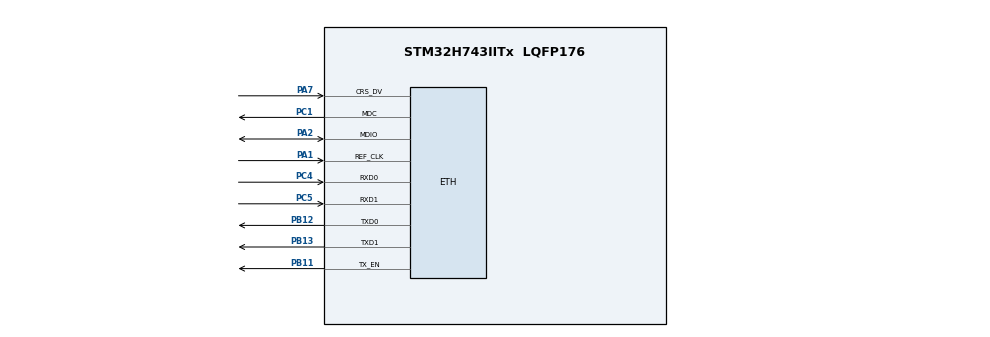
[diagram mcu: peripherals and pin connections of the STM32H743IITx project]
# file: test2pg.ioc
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CORTEX_M7.BaseAddress-Cortex_Memory_Protection_Unit_Region0_Settings=0x30040000
CORTEX_M7.BaseAddress-Cortex_Memory_Protection_Unit_Region1_Settings=0x30040000
CORTEX_M7.CPU_DCache=Enabled
CORTEX_M7.CPU_ICache=Enabled
CORTEX_M7.DisableExec-Cortex_Memory_Protection_Unit_Region0_Settings=MPU_INSTRUCTION_ACCESS_DISABLE
CORTEX_M7.DisableExec-Cortex_Memory_Protection_Unit_Region1_Settings=MPU_INSTRUCTION_ACCESS_ENABLE
CORTEX_M7.Enable-Cortex_Memory_Protection_Unit_Region0_Settings=MPU_REGION_ENABLE
CORTEX_M7.Enable-Cortex_Memory_Protection_Unit_Region1_Settings=MPU_REGION_ENABLE
CORTEX_M7.IsBufferable-Cortex_Memory_Protection_Unit_Region0_Settings=MPU_ACCESS_BUFFERABLE
CORTEX_M7.IsBufferable-Cortex_Memory_Protection_Unit_Region1_Settings=MPU_ACCESS_NOT_BUFFERABLE
CORTEX_M7.IsCacheable-Cortex_Memory_Protection_Unit_Region1_Settings=MPU_ACCESS_CACHEABLE
CORTEX_M7.IsShareable-Cortex_Memory_Protection_Unit_Region0_Settings=MPU_ACCESS_SHAREABLE
CORTEX_M7.IsShareable-Cortex_Memory_Protection_Unit_Region1_Settings=MPU_ACCESS_NOT_SHAREABLE
CORTEX_M7.MPU_Control=MPU_PRIVILEGED_DEFAULT
CORTEX_M7.Size-Cortex_Memory_Protection_Unit_Region0_Settings=MPU_REGION_SIZE_256B
CORTEX_M7.Size-Cortex_Memory_Protection_Unit_Region1_Settings=MPU_REGION_SIZE_16KB
ETH.MediaInterface=HAL_ETH_RMII_MODE
FREERTOS.Tasks01=defaultTask,0,1024,StartDefaultTask,Default,NULL,Dynamic,NULL,NULL
LWIP.BSP.number=1
LWIP.MEM_SIZE=16360
LWIP.Version=v2.1.2_Cube
LWIP0.BSP.STBoard=false
LWIP0.BSP.api=BSP_COMPONENT_DRIVER
LWIP0.BSP.component=LAN8742
LWIP0.BSP.i2caddr=0
LWIP0.BSP.instance=LAN8742
LWIP0.BSP.name=Driver_PHY
LWIP0.BSP.solution=LAN8742
Mcu.Family=STM32H7
Mcu.Name=STM32H743IITx
Mcu.Package=LQFP176
NVIC.ETH_IRQn=true\:5\:0\:false\:false\:true\:true\:true\:true
NVIC.PriorityGroup=NVIC_PRIORITYGROUP_4
PA1.Mode=RMII
PA1.Signal=ETH_REF_CLK
PA2.Mode=RMII
PA2.Signal=ETH_MDIO
PA7.Mode=RMII
PA7.Signal=ETH_CRS_DV
PB11.Mode=RMII
PB11.Signal=ETH_TX_EN
PB12.Mode=RMII
PB12.Signal=ETH_TXD0
PB13.Mode=RMII
PB13.Signal=ETH_TXD1
PC1.Mode=RMII
PC1.Signal=ETH_MDC
PC4.Mode=RMII
PC4.Signal=ETH_RXD0
PC5.Mode=RMII
PC5.Signal=ETH_RXD1
PH0-OSC_IN\ (PH0).Mode=HSE-External-Oscillator
PH0-OSC_IN\ (PH0).Signal=RCC_OSC_IN
PH1-OSC_OUT\ (PH1).Mode=HSE-External-Oscillator
PH1-OSC_OUT\ (PH1).Signal=RCC_OSC_OUT
ProjectManager.HeapSize=0x200
ProjectManager.StackSize=0x400
ProjectManager.TargetToolchain=STM32CubeIDE
RCC.ADCFreq_Value=50390625
RCC.APB1Freq_Value=120000000
RCC.APB2Freq_Value=120000000
RCC.APB3Freq_Value=120000000
RCC.APB4Freq_Value=120000000
RCC.CortexFreq_Value=480000000
RCC.D1PPRE=RCC_APB3_DIV2
RCC.D2PPRE1=RCC_APB1_DIV2
RCC.D2PPRE2=RCC_APB2_DIV2
RCC.D3PPRE=RCC_APB4_DIV2
RCC.DIVM1=5
RCC.DIVN1=192
RCC.HCLKFreq_Value=240000000
RCC.HPRE=RCC_HCLK_DIV2
RCC.HSE_VALUE=25000000
RCC.PLLSourceVirtual=RCC_PLLSOURCE_HSE
RCC.SYSCLKFreq_VALUE=480000000
RCC.SYSCLKSource=RCC_SYSCLKSOURCE_PLLCLK
RCC.USBFreq_Value=480000000
VP_FREERTOS_VS_CMSIS_V1.Mode=CMSIS_V1
VP_LWIP_VS_Enabled.Mode=Enabled
board=custom

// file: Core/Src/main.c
/* USER CODE BEGIN Header */
/**
  ******************************************************************************
  * @file           : main.c
  * @brief          : Main program body
  ******************************************************************************
  * @attention
  *
  * Copyright (c) 2022 STMicroelectronics.
  * All rights reserved.
  *
  * This software is licensed under terms that can be found in the LICENSE file
  * in the root directory of this software component.
  * If no LICENSE file comes with this software, it is provided AS-IS.
  *
  ******************************************************************************
  */
/* USER CODE END Header */
#include "main.h"
#include "cmsis_os.h"
#include "lwip.h"
#include "bsp_init.h"

osThreadId defaultTaskHandle;

void SystemClock_Config(void);
static void MPU_Config(void);
static void MX_GPIO_Init(void);
void StartDefaultTask(void const * argument);

TaskHandle_t AppTaskCreate_Handle          = NULL;      //创建线程句柄

void Cache_Enable(void)
{
    SCB_EnableICache();//使能I-Cache
    SCB_EnableDCache();//使能D-Cache
	SCB->CACR|=1<<2;   //强制D-Cache透写,如不开启,实际使用中可能遇到各种问题
}
int main(void)
{

  /* MPU Configuration--------------------------------------------------------*/
  MPU_Config();

  Cache_Enable();

  /* MCU Configuration--------------------------------------------------------*/

  /* Reset of all peripherals, Initializes the Flash interface and the Systick. */
  HAL_Init();

  /* Configure the system clock */
  SystemClock_Config();

  /* Initialize all configured peripherals */
  MX_GPIO_Init();
  /* USER CODE BEGIN 2 */
  MX_TIM6_Init(10000-1, 24000-1);
  /* USER CODE END 2 */

  /* Create the thread(s) */
  /* definition and creation of defaultTask */
//  osThreadDef(defaultTask, StartDefaultTask, osPriorityNormal, 0, 1024);
//  defaultTaskHandle = osThreadCreate(osThread(defaultTask), NULL);
//
//  /* USER CODE BEGIN RTOS_THREADS */
//  /* add threads, ... */
//  /* USER CODE END RTOS_THREADS */
//
//  /* Start scheduler */
 // osKernelStart();

	BaseType_t xReturn = pdPASS;/* 定义一个创建信息返回值，默认为pdPASS */
	/*创建各个线程*/
	xReturn = xTaskCreate((TaskFunction_t) AppTaskCreate,
						  (const char*   ) "AppTaskCreate",
						  (uint16_t      ) 512,
						  (void*         ) NULL,
						  (UBaseType_t   ) 1,
						  (TaskHandle_t* ) &AppTaskCreate_Handle);
	/* 启动任务调度 */
	if (pdPASS == xReturn)
	{
		/* 启动任务，开启调度 */
		vTaskStartScheduler();
	}
	else
		return -1;
  while (1)
  {
    /* USER CODE END WHILE */

  }
}

void SystemClock_Config(void)
{
  RCC_OscInitTypeDef RCC_OscInitStruct = {0};
  RCC_ClkInitTypeDef RCC_ClkInitStruct = {0};

  /** Supply configuration update enable
  */
  HAL_PWREx_ConfigSupply(PWR_LDO_SUPPLY);
  /** Configure the main internal regulator output voltage
  */
  __HAL_PWR_VOLTAGESCALING_CONFIG(PWR_REGULATOR_VOLTAGE_SCALE0);

  while(!__HAL_PWR_GET_FLAG(PWR_FLAG_VOSRDY)) {}
  /** Initializes the RCC Oscillators according to the specified parameters
  * in the RCC_OscInitTypeDef structure.
  */
  RCC_OscInitStruct.OscillatorType = RCC_OSCILLATORTYPE_HSE;
  RCC_OscInitStruct.HSEState = RCC_HSE_ON;
  RCC_OscInitStruct.PLL.PLLState = RCC_PLL_ON;
  RCC_OscInitStruct.PLL.PLLSource = RCC_PLLSOURCE_HSE;
  RCC_OscInitStruct.PLL.PLLM = 5;
  RCC_OscInitStruct.PLL.PLLN = 192;
  RCC_OscInitStruct.PLL.PLLP = 2;
  RCC_OscInitStruct.PLL.PLLQ = 2;
  RCC_OscInitStruct.PLL.PLLR = 2;
  RCC_OscInitStruct.PLL.PLLRGE = RCC_PLL1VCIRANGE_2;
  RCC_OscInitStruct.PLL.PLLVCOSEL = RCC_PLL1VCOWIDE;
  RCC_OscInitStruct.PLL.PLLFRACN = 0;
  if (HAL_RCC_OscConfig(&RCC_OscInitStruct) != HAL_OK)
  {
    Error_Handler();
  }
  /** Initializes the CPU, AHB and APB buses clocks
  */
  RCC_ClkInitStruct.ClockType = RCC_CLOCKTYPE_HCLK|RCC_CLOCKTYPE_SYSCLK
                              |RCC_CLOCKTYPE_PCLK1|RCC_CLOCKTYPE_PCLK2
                              |RCC_CLOCKTYPE_D3PCLK1|RCC_CLOCKTYPE_D1PCLK1;
  RCC_ClkInitStruct.SYSCLKSource = RCC_SYSCLKSOURCE_PLLCLK;
  RCC_ClkInitStruct.SYSCLKDivider = RCC_SYSCLK_DIV1;
  RCC_ClkInitStruct.AHBCLKDivider = RCC_HCLK_DIV2;
  RCC_ClkInitStruct.APB3CLKDivider = RCC_APB3_DIV2;
  RCC_ClkInitStruct.APB1CLKDivider = RCC_APB1_DIV2;
  RCC_ClkInitStruct.APB2CLKDivider = RCC_APB2_DIV2;
  RCC_ClkInitStruct.APB4CLKDivider = RCC_APB4_DIV2;

  if (HAL_RCC_ClockConfig(&RCC_ClkInitStruct, FLASH_LATENCY_4) != HAL_OK)
  {
    Error_Handler();
  }
}

static void MX_GPIO_Init(void)
{

  GPIO_InitTypeDef GPIO_InitStruct = {0};

  /* GPIO Ports Clock Enable */
  __HAL_RCC_GPIOC_CLK_ENABLE();
  __HAL_RCC_GPIOF_CLK_ENABLE();
  __HAL_RCC_GPIOH_CLK_ENABLE();
  __HAL_RCC_GPIOA_CLK_ENABLE();
  __HAL_RCC_GPIOG_CLK_ENABLE();
  __HAL_RCC_GPIOE_CLK_ENABLE();
  __HAL_RCC_GPIOB_CLK_ENABLE();
  __HAL_RCC_GPIOD_CLK_ENABLE();

  /*Configure GPIO pin Output Level */
  HAL_GPIO_WritePin(GPIOH, GPIO_PIN_10|GPIO_PIN_11|GPIO_PIN_12, GPIO_PIN_SET);

  /* LED */
  GPIO_InitStruct.Pin = GPIO_PIN_10|GPIO_PIN_11|GPIO_PIN_12;
  GPIO_InitStruct.Mode = GPIO_MODE_OUTPUT_PP;
  GPIO_InitStruct.Pull = GPIO_PULLUP;
  GPIO_InitStruct.Speed = GPIO_SPEED_FREQ_VERY_HIGH;
  HAL_GPIO_Init(GPIOH, &GPIO_InitStruct);

  /* KEY */
  /*选择按键的引脚*/
  GPIO_InitStruct.Pin = GPIO_PIN_0;
  /*设置引脚为输入模式*/
  GPIO_InitStruct.Mode = GPIO_MODE_INPUT;
  /*设置引脚不上拉也不下拉*/
  GPIO_InitStruct.Pull = GPIO_NOPULL;
  /*使用上面的结构体初始化按键*/
  HAL_GPIO_Init(GPIOA, &GPIO_InitStruct);
  /*选择按键的引脚*/
  GPIO_InitStruct.Pin = GPIO_PIN_13;
  /*使用上面的结构体初始化按键*/
  HAL_GPIO_Init(GPIOC, &GPIO_InitStruct);

}

void StartDefaultTask(void const * argument)
{
  /* init code for LWIP */
  MX_LWIP_Init();
  for(;;)
  {
    osDelay(1);
  }
}

/* MPU Configuration */

void MPU_Config(void)
{
  MPU_Region_InitTypeDef MPU_InitStruct = {0};

  /* Disables the MPU */
  HAL_MPU_Disable();
  /** Initializes and configures the Region and the memory to be protected
  */
  MPU_InitStruct.Enable = MPU_REGION_ENABLE;
  MPU_InitStruct.Number = MPU_REGION_NUMBER0;
  MPU_InitStruct.BaseAddress = 0x30040000;
  MPU_InitStruct.Size = MPU_REGION_SIZE_256B;
  MPU_InitStruct.SubRegionDisable = 0x0;
  MPU_InitStruct.TypeExtField = MPU_TEX_LEVEL0;
  MPU_InitStruct.AccessPermission = MPU_REGION_NO_ACCESS;
  MPU_InitStruct.DisableExec = MPU_INSTRUCTION_ACCESS_DISABLE;
  MPU_InitStruct.IsShareable = MPU_ACCESS_SHAREABLE;
  MPU_InitStruct.IsCacheable = MPU_ACCESS_NOT_CACHEABLE;
  MPU_InitStruct.IsBufferable = MPU_ACCESS_BUFFERABLE;

  HAL_MPU_ConfigRegion(&MPU_InitStruct);
  /** Initializes and configures the Region and the memory to be protected
  */
  MPU_InitStruct.Number = MPU_REGION_NUMBER1;
  MPU_InitStruct.Size = MPU_REGION_SIZE_16KB;
  MPU_InitStruct.DisableExec = MPU_INSTRUCTION_ACCESS_ENABLE;
  MPU_InitStruct.IsShareable = MPU_ACCESS_NOT_SHAREABLE;
  MPU_InitStruct.IsCacheable = MPU_ACCESS_CACHEABLE;
  MPU_InitStruct.IsBufferable = MPU_ACCESS_NOT_BUFFERABLE;

  HAL_MPU_ConfigRegion(&MPU_InitStruct);
  /* Enables the MPU */
  HAL_MPU_Enable(MPU_PRIVILEGED_DEFAULT);

}

void Error_Handler(void)
{
  __disable_irq();
  while (1)
  {
  }
}

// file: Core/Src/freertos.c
/* USER CODE BEGIN Header */
/**
  ******************************************************************************
  * File Name          : freertos.c
  * Description        : Code for freertos applications
  ******************************************************************************
  * @attention
  *
  * Copyright (c) 2022 STMicroelectronics.
  * All rights reserved.
  *
  * This software is licensed under terms that can be found in the LICENSE file
  * in the root directory of this software component.
  * If no LICENSE file comes with this software, it is provided AS-IS.
  *
  ******************************************************************************
  */
/* USER CODE END Header */

#include "FreeRTOS.h"
#include "task.h"
#include "main.h"

/* GetIdleTaskMemory prototype (linked to static allocation support) */
void vApplicationGetIdleTaskMemory( StaticTask_t **ppxIdleTaskTCBBuffer, StackType_t **ppxIdleTaskStackBuffer, uint32_t *pulIdleTaskStackSize );

/* USER CODE BEGIN GET_IDLE_TASK_MEMORY */
static StaticTask_t xIdleTaskTCBBuffer;
static StackType_t xIdleStack[configMINIMAL_STACK_SIZE];

void vApplicationGetIdleTaskMemory( StaticTask_t **ppxIdleTaskTCBBuffer, StackType_t **ppxIdleTaskStackBuffer, uint32_t *pulIdleTaskStackSize )
{
  *ppxIdleTaskTCBBuffer = &xIdleTaskTCBBuffer;
  *ppxIdleTaskStackBuffer = &xIdleStack[0];
  *pulIdleTaskStackSize = configMINIMAL_STACK_SIZE;
  /* place for user code */
}
/* USER CODE END GET_IDLE_TASK_MEMORY */

/* Private application code --------------------------------------------------*/// FreeRTOSConfig.h
